VERSION 5.7 ;
  NOWIREEXTENSIONATPIN ON ;
  DIVIDERCHAR "/" ;
  BUSBITCHARS "[]" ;
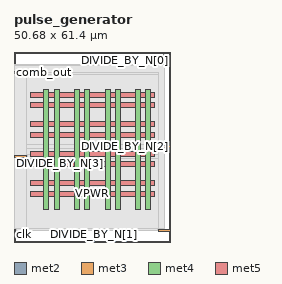
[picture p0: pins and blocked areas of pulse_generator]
MACRO pulse_generator
  CLASS BLOCK ;
  FOREIGN pulse_generator ;
  ORIGIN 0.000 0.000 ;
  SIZE 50.680 BY 61.400 ;
  PIN DIVIDE_BY_N[0]
    DIRECTION INPUT ;
    USE SIGNAL ;
    ANTENNAGATEAREA 0.247500 ;
    PORT
      LAYER met2 ;
        RECT 48.390 57.400 48.670 61.400 ;
    END
  END DIVIDE_BY_N[0]
  PIN DIVIDE_BY_N[1]
    DIRECTION INPUT ;
    USE SIGNAL ;
    ANTENNAGATEAREA 0.213000 ;
    PORT
      LAYER met2 ;
        RECT 25.850 0.000 26.130 4.000 ;
    END
  END DIVIDE_BY_N[1]
  PIN DIVIDE_BY_N[2]
    DIRECTION INPUT ;
    USE SIGNAL ;
    ANTENNAGATEAREA 0.213000 ;
    PORT
      LAYER met3 ;
        RECT 46.680 30.640 50.680 31.240 ;
    END
  END DIVIDE_BY_N[2]
  PIN DIVIDE_BY_N[3]
    DIRECTION INPUT ;
    USE SIGNAL ;
    ANTENNAGATEAREA 0.495000 ;
    PORT
      LAYER met3 ;
        RECT 0.000 27.240 4.000 27.840 ;
    END
  END DIVIDE_BY_N[3]
  PIN VGND
    DIRECTION INOUT ;
    USE GROUND ;
    PORT
      LAYER met4 ;
        RECT 12.965 10.640 14.565 49.200 ;
    END
    PORT
      LAYER met4 ;
        RECT 22.855 10.640 24.455 49.200 ;
    END
    PORT
      LAYER met4 ;
        RECT 32.745 10.640 34.345 49.200 ;
    END
    PORT
      LAYER met4 ;
        RECT 42.635 10.640 44.235 49.200 ;
    END
    PORT
      LAYER met5 ;
        RECT 5.280 18.140 45.320 19.740 ;
    END
    PORT
      LAYER met5 ;
        RECT 5.280 27.660 45.320 29.260 ;
    END
    PORT
      LAYER met5 ;
        RECT 5.280 37.180 45.320 38.780 ;
    END
    PORT
      LAYER met5 ;
        RECT 5.280 46.700 45.320 48.300 ;
    END
  END VGND
  PIN VPWR
    DIRECTION INOUT ;
    USE POWER ;
    PORT
      LAYER met4 ;
        RECT 9.665 10.640 11.265 49.200 ;
    END
    PORT
      LAYER met4 ;
        RECT 19.555 10.640 21.155 49.200 ;
    END
    PORT
      LAYER met4 ;
        RECT 29.445 10.640 31.045 49.200 ;
    END
    PORT
      LAYER met4 ;
        RECT 39.335 10.640 40.935 49.200 ;
    END
    PORT
      LAYER met5 ;
        RECT 5.280 14.840 45.320 16.440 ;
    END
    PORT
      LAYER met5 ;
        RECT 5.280 24.360 45.320 25.960 ;
    END
    PORT
      LAYER met5 ;
        RECT 5.280 33.880 45.320 35.480 ;
    END
    PORT
      LAYER met5 ;
        RECT 5.280 43.400 45.320 45.000 ;
    END
  END VPWR
  PIN clk
    DIRECTION INPUT ;
    USE SIGNAL ;
    ANTENNAGATEAREA 0.852000 ;
    PORT
      LAYER met2 ;
        RECT 0.090 0.000 0.370 4.000 ;
    END
  END clk
  PIN comb_out
    DIRECTION OUTPUT TRISTATE ;
    USE SIGNAL ;
    ANTENNADIFFAREA 1.336500 ;
    PORT
      LAYER met3 ;
        RECT 0.000 54.440 4.000 55.040 ;
    END
  END comb_out
  PIN rst
    DIRECTION INPUT ;
    USE SIGNAL ;
    ANTENNAGATEAREA 0.196500 ;
    PORT
      LAYER met2 ;
        RECT 22.630 57.400 22.910 61.400 ;
    END
  END rst
  PIN sync_out
    DIRECTION OUTPUT TRISTATE ;
    USE SIGNAL ;
    ANTENNADIFFAREA 0.795200 ;
    PORT
      LAYER met3 ;
        RECT 46.680 3.440 50.680 4.040 ;
    END
  END sync_out
  OBS
      LAYER li1 ;
        RECT 5.520 10.795 45.080 49.045 ;
      LAYER met1 ;
        RECT 0.070 10.640 48.690 49.200 ;
      LAYER met2 ;
        RECT 0.100 57.120 22.350 57.400 ;
        RECT 23.190 57.120 48.110 57.400 ;
        RECT 0.100 4.280 48.660 57.120 ;
        RECT 0.650 3.555 25.570 4.280 ;
        RECT 26.410 3.555 48.660 4.280 ;
      LAYER met3 ;
        RECT 4.400 54.040 46.680 54.890 ;
        RECT 4.000 31.640 46.680 54.040 ;
        RECT 4.000 30.240 46.280 31.640 ;
        RECT 4.000 28.240 46.680 30.240 ;
        RECT 4.400 26.840 46.680 28.240 ;
        RECT 4.000 4.440 46.680 26.840 ;
        RECT 4.000 3.575 46.280 4.440 ;
  END
END pulse_generator
END LIBRARY

